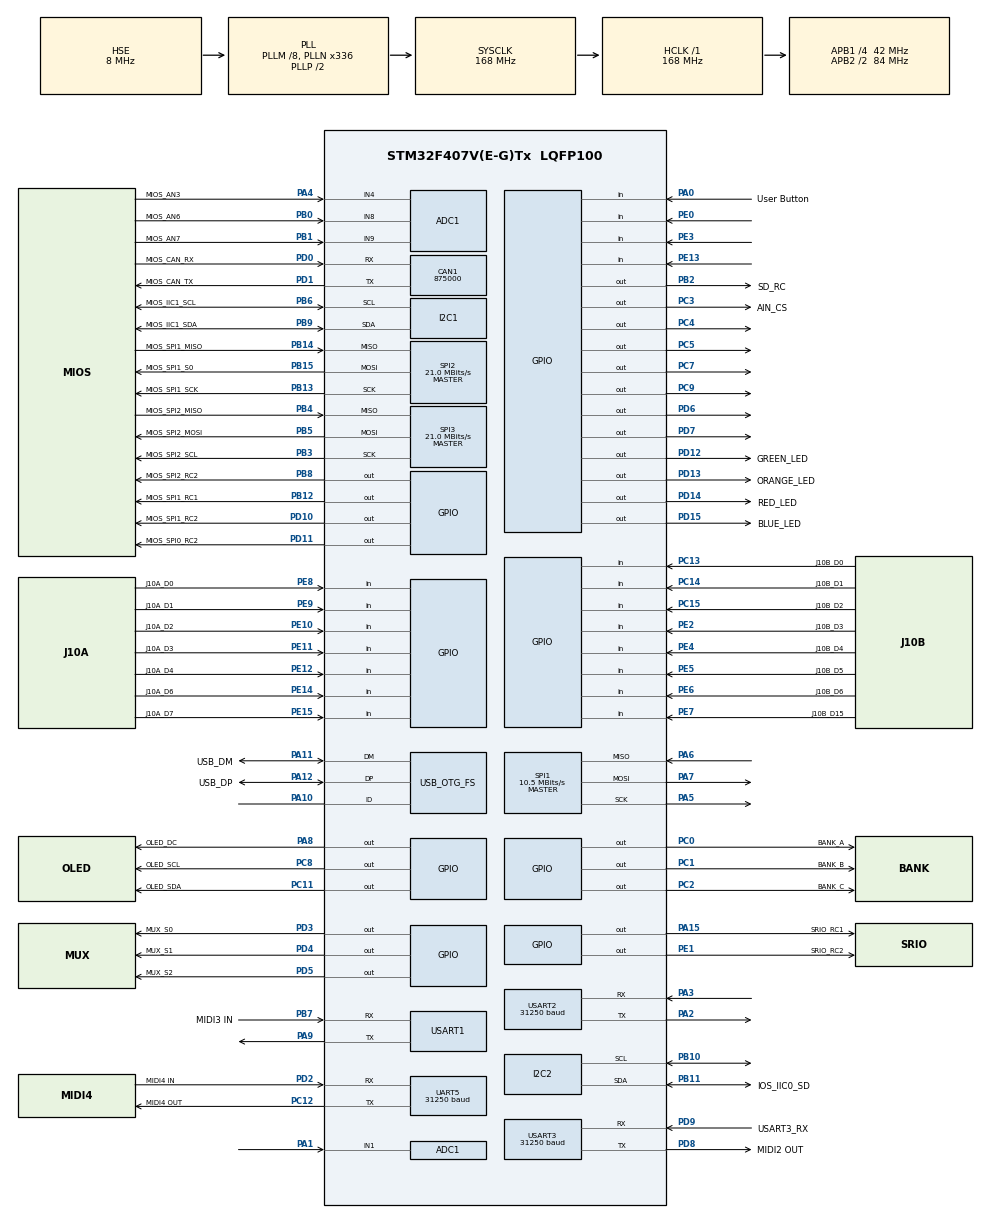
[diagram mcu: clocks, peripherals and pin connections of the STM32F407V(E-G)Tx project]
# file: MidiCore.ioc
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ADC1.Channel-0\#ChannelRegularConversion=ADC_CHANNEL_1
ADC1.NbrOfConversionFlag=1
ADC1.Rank-0\#ChannelRegularConversion=1
ADC1.SamplingTime-0\#ChannelRegularConversion=ADC_SAMPLETIME_3CYCLES
ADC1.master=1
CAN1.BS1=CAN_BS1_1TQ
CAN1.BS2=CAN_BS2_1TQ
CAN1.CalculateBaudRate=875000
CAN1.CalculateTimeBit=1142
CAN1.CalculateTimeQuantum=380.95238095238096
Dma.Request0=USART3_RX
Dma.Request1=SPI1_RX
Dma.Request2=SPI1_TX
Dma.SPI1_RX.1.Direction=DMA_PERIPH_TO_MEMORY
Dma.SPI1_RX.1.FIFOMode=DMA_FIFOMODE_DISABLE
Dma.SPI1_RX.1.Instance=DMA2_Stream0
Dma.SPI1_RX.1.MemDataAlignment=DMA_MDATAALIGN_BYTE
Dma.SPI1_RX.1.MemInc=DMA_MINC_ENABLE
Dma.SPI1_RX.1.Mode=DMA_NORMAL
Dma.SPI1_RX.1.PeriphDataAlignment=DMA_PDATAALIGN_BYTE
Dma.SPI1_RX.1.PeriphInc=DMA_PINC_DISABLE
Dma.SPI1_RX.1.Priority=DMA_PRIORITY_LOW
Dma.SPI1_TX.2.Direction=DMA_MEMORY_TO_PERIPH
Dma.SPI1_TX.2.FIFOMode=DMA_FIFOMODE_DISABLE
Dma.SPI1_TX.2.Instance=DMA2_Stream3
Dma.SPI1_TX.2.MemDataAlignment=DMA_MDATAALIGN_BYTE
Dma.SPI1_TX.2.MemInc=DMA_MINC_ENABLE
Dma.SPI1_TX.2.Mode=DMA_NORMAL
Dma.SPI1_TX.2.PeriphDataAlignment=DMA_PDATAALIGN_BYTE
Dma.SPI1_TX.2.PeriphInc=DMA_PINC_DISABLE
Dma.SPI1_TX.2.Priority=DMA_PRIORITY_LOW
Dma.USART3_RX.0.Direction=DMA_PERIPH_TO_MEMORY
Dma.USART3_RX.0.FIFOMode=DMA_FIFOMODE_DISABLE
Dma.USART3_RX.0.Instance=DMA1_Stream1
Dma.USART3_RX.0.MemDataAlignment=DMA_MDATAALIGN_BYTE
Dma.USART3_RX.0.MemInc=DMA_MINC_ENABLE
Dma.USART3_RX.0.Mode=DMA_NORMAL
Dma.USART3_RX.0.PeriphDataAlignment=DMA_PDATAALIGN_BYTE
Dma.USART3_RX.0.PeriphInc=DMA_PINC_DISABLE
Dma.USART3_RX.0.Priority=DMA_PRIORITY_LOW
FREERTOS.Tasks01=defaultTask,24,256,StartDefaultTask,Default,NULL,Dynamic,NULL,NULL
FREERTOS.configTOTAL_HEAP_SIZE=40960
FREERTOS.configUSE_MALLOC_FAILED_HOOK=0
FREERTOS.configUSE_NEWLIB_REENTRANT=1
Mcu.Family=STM32F4
Mcu.Name=STM32F407V(E-G)Tx
Mcu.Package=LQFP100
NVIC.DMA1_Stream1_IRQn=true\:5\:0\:false\:false\:true\:true\:false\:true\:true
NVIC.DMA2_Stream0_IRQn=true\:5\:0\:false\:false\:true\:true\:false\:true\:true
NVIC.DMA2_Stream3_IRQn=true\:5\:0\:false\:false\:true\:true\:false\:true\:true
NVIC.PriorityGroup=NVIC_PRIORITYGROUP_4
NVIC.TIM6_DAC_IRQn=true\:15\:0\:false\:false\:true\:false\:false\:true\:true
NVIC.TimeBase=TIM6_DAC_IRQn
NVIC.TimeBaseIP=TIM6
PA0-WKUP.GPIO_Label=User Button
PA0-WKUP.Signal=GPIO_Input
PA1.Signal=ADCx_IN1
PA10.Mode=OTG/Dual_Role_Device
PA10.Signal=USB_OTG_FS_ID
PA11.GPIO_Label=USB_DM
PA11.Mode=OTG/Dual_Role_Device
PA11.Signal=USB_OTG_FS_DM
PA12.GPIO_Label=USB_DP
PA12.Mode=OTG/Dual_Role_Device
PA12.Signal=USB_OTG_FS_DP
PA13.Mode=Serial_Wire
PA13.Signal=SYS_JTMS-SWDIO
PA14.GPIO_Label=MIOS_SPI2_RC1
PA14.Mode=Serial_Wire
PA14.Signal=SYS_JTCK-SWCLK
PA15.GPIO_Label=SRIO_RC1
PA15.Signal=GPIO_Output
PA2.Mode=Asynchronous
PA2.Signal=USART2_TX
PA3.Mode=Asynchronous
PA3.Signal=USART2_RX
PA4.GPIO_Label=MIOS_AN3
PA4.Signal=ADCx_IN4
PA5.Mode=Full_Duplex_Master
PA5.Signal=SPI1_SCK
PA6.Mode=Full_Duplex_Master
PA6.Signal=SPI1_MISO
PA7.Mode=Full_Duplex_Master
PA7.Signal=SPI1_MOSI
PA8.GPIO_Label=OLED_DC
PA8.Signal=GPIO_Output
PA9.Mode=Asynchronous
PA9.Signal=USART1_TX
PB0.GPIO_Label=MIOS_AN6
PB0.Signal=ADCx_IN8
PB1.GPIO_Label=MIOS_AN7
PB1.Signal=ADCx_IN9
PB10.Mode=I2C
PB10.Signal=I2C2_SCL
PB11.GPIO_Label=IOS_IIC0_SD
PB11.Mode=I2C
PB11.Signal=I2C2_SDA
PB12.GPIO_Label=MIOS_SPI1_RC1
PB12.Signal=GPIO_Output
PB13.GPIO_Label=MIOS_SPI1_SCK
PB13.Mode=Full_Duplex_Master
PB13.Signal=SPI2_SCK
PB14.GPIO_Label=MIOS_SPI1_MISO
PB14.Mode=Full_Duplex_Master
PB14.Signal=SPI2_MISO
PB15.GPIO_Label=MIOS_SPI1_S0
PB15.Mode=Full_Duplex_Master
PB15.Signal=SPI2_MOSI
PB2.GPIO_Label=SD_RC
PB2.Signal=GPIO_Output
PB3.GPIO_Label=MIOS_SPI2_SCL
PB3.Mode=Full_Duplex_Master
PB3.Signal=SPI3_SCK
PB4.GPIO_Label=MIOS_SPI2_MISO
PB4.Mode=Full_Duplex_Master
PB4.Signal=SPI3_MISO
PB5.GPIO_Label=MIOS_SPI2_MOSI
PB5.Mode=Full_Duplex_Master
PB5.Signal=SPI3_MOSI
PB6.GPIO_Label=MIOS_IIC1_SCL
PB6.Mode=I2C
PB6.Signal=I2C1_SCL
PB7.GPIO_Label=MIDI3 IN
PB7.Mode=Asynchronous
PB7.Signal=USART1_RX
PB8.GPIO_Label=MIOS_SPI2_RC2
PB8.Signal=GPIO_Output
PB9.GPIO_Label=MIOS_IIC1_SDA
PB9.Mode=I2C
PB9.Signal=I2C1_SDA
PC0.GPIO_Label=BANK_A
PC0.Signal=GPIO_Output
PC1.GPIO_Label=BANK_B
PC1.Signal=GPIO_Output
PC11.GPIO_Label=OLED_SDA
PC11.Signal=GPIO_Output
PC12.GPIO_Label=MIDI4 OUT
PC12.Mode=Asynchronous
PC12.Signal=UART5_TX
PC13-ANTI_TAMP.GPIO_Label=J10B_D0
PC13-ANTI_TAMP.Signal=GPIO_Input
PC14-OSC32_IN.GPIO_Label=J10B_D1
PC14-OSC32_IN.Signal=GPIO_Input
PC15-OSC32_OUT.GPIO_Label=J10B_D2
PC15-OSC32_OUT.Signal=GPIO_Input
PC2.GPIO_Label=BANK_C
PC2.Signal=GPIO_Output
PC3.GPIO_Label=AIN_CS
PC3.Signal=GPIO_Output
PC4.Signal=GPIO_Output
PC5.Signal=GPIO_Output
PC6.GPIO_Label=MIDI3 OUT
PC6.Signal=USART6_TX
PC7.Signal=GPIO_Output
PC8.GPIO_Label=OLED_SCL
PC8.Signal=GPIO_Output
PC9.Signal=GPIO_Output
PD0.GPIO_Label=MIOS_CAN_RX
PD0.Mode=CAN_Activate
PD0.Signal=CAN1_RX
PD1.GPIO_Label=MIOS_CAN_TX
PD1.Mode=CAN_Activate
PD1.Signal=CAN1_TX
PD10.GPIO_Label=MIOS_SPI1_RC2
PD10.Signal=GPIO_Output
PD11.GPIO_Label=MIOS_SPI0_RC2
PD11.Signal=GPIO_Output
PD12.GPIO_Label=GREEN_LED
PD12.Signal=GPIO_Output
PD13.GPIO_Label=ORANGE_LED
PD13.Signal=GPIO_Output
PD14.GPIO_Label=RED_LED
PD14.Signal=GPIO_Output
PD15.GPIO_Label=BLUE_LED
PD15.Signal=GPIO_Output
PD2.GPIO_Label=MIDI4 IN
PD2.Mode=Asynchronous
PD2.Signal=UART5_RX
PD3.GPIO_Label=MUX_S0
PD3.Signal=GPIO_Output
PD4.GPIO_Label=MUX_S1
PD4.Signal=GPIO_Output
PD5.GPIO_Label=MUX_S2
PD5.Signal=GPIO_Output
PD6.Signal=GPIO_Output
PD7.Signal=GPIO_Output
PD8.GPIO_Label=MIDI2 OUT
PD8.Mode=Asynchronous
PD8.Signal=USART3_TX
PD9.GPIO_Label=USART3_RX
PD9.Mode=Asynchronous
PD9.Signal=USART3_RX
PE0.Signal=GPIO_Input
PE1.GPIO_Label=SRIO_RC2
PE1.Signal=GPIO_Output
PE10.GPIO_Label=J10A_D2
PE10.Signal=GPIO_Input
PE11.GPIO_Label=J10A_D3
PE11.Signal=GPIO_Input
PE12.GPIO_Label=J10A_D4
PE12.Signal=GPIO_Input
PE13.Signal=GPIO_Input
PE14.GPIO_Label=J10A_D6
PE14.Signal=GPIO_Input
PE15.GPIO_Label=J10A_D7
PE15.Signal=GPIO_Input
PE2.GPIO_Label=J10B_D3
PE2.Signal=GPIO_Input
PE3.Signal=GPIO_Input
PE4.GPIO_Label=J10B_D4
PE4.Signal=GPIO_Input
PE5.GPIO_Label=J10B_D5
PE5.Signal=GPIO_Input
PE6.GPIO_Label=J10B_D6
PE6.Signal=GPIO_Input
PE7.GPIO_Label=J10B_D15
PE7.Signal=GPIO_Input
PE8.GPIO_Label=J10A_D0
PE8.Signal=GPIO_Input
PE9.GPIO_Label=J10A_D1
PE9.Signal=GPIO_Input
PH0-OSC_IN.Mode=HSE-External-Oscillator
PH0-OSC_IN.Signal=RCC_OSC_IN
PH1-OSC_OUT.Mode=HSE-External-Oscillator
PH1-OSC_OUT.Signal=RCC_OSC_OUT
ProjectManager.HeapSize=0x200
ProjectManager.StackSize=0x400
ProjectManager.TargetToolchain=STM32CubeIDE
RCC.48MHZClocksFreq_Value=48000000
RCC.AHBFreq_Value=168000000
RCC.APB1CLKDivider=RCC_HCLK_DIV4
RCC.APB1Freq_Value=42000000
RCC.APB1TimFreq_Value=84000000
RCC.APB2CLKDivider=RCC_HCLK_DIV2
RCC.APB2Freq_Value=84000000
RCC.APB2TimFreq_Value=168000000
RCC.CortexFreq_Value=168000000
RCC.EnbaleCSS=true
RCC.HCLKFreq_Value=168000000
RCC.HSE_VALUE=8000000
RCC.HSI_VALUE=16000000
RCC.LSE_VALUE=32768
RCC.PLLM=8
RCC.PLLN=336
RCC.PLLQ=7
RCC.PLLSourceVirtual=RCC_PLLSOURCE_HSE
RCC.SYSCLKFreq_VALUE=168000000
RCC.SYSCLKSource=RCC_SYSCLKSOURCE_PLLCLK
RCC.VCOOutputFreq_Value=336000000
SH.ADCx_IN1.0=ADC1_IN1,IN1
SH.ADCx_IN4.0=ADC1_IN4,IN4
SH.ADCx_IN8.0=ADC1_IN8,IN8
SH.ADCx_IN9.0=ADC1_IN9,IN9
SPI1.BaudRatePrescaler=SPI_BAUDRATEPRESCALER_8
SPI1.CalculateBaudRate=10.5 MBits/s
SPI1.Direction=SPI_DIRECTION_2LINES
SPI1.Mode=SPI_MODE_MASTER
SPI1.VirtualType=VM_MASTER
SPI2.BaudRatePrescaler=SPI_BAUDRATEPRESCALER_2
SPI2.CalculateBaudRate=21.0 MBits/s
SPI2.Direction=SPI_DIRECTION_2LINES
SPI2.Mode=SPI_MODE_MASTER
SPI2.VirtualType=VM_MASTER
SPI3.BaudRatePrescaler=SPI_BAUDRATEPRESCALER_2
SPI3.CalculateBaudRate=21.0 MBits/s
SPI3.Direction=SPI_DIRECTION_2LINES
SPI3.Mode=SPI_MODE_MASTER
SPI3.VirtualType=VM_MASTER
UART5.BaudRate=31250
UART5.VirtualMode=Asynchronous
USART1.VirtualMode=VM_ASYNC
USART2.BaudRate=31250
USART2.VirtualMode=VM_ASYNC
USART3.BaudRate=31250
USART3.VirtualMode=VM_ASYNC
VP_FATFS_VS_Generic.Mode=User_defined
VP_FREERTOS_VS_CMSIS_V2.Mode=CMSIS_V2
VP_SYS_VS_tim6.Mode=TIM6
VP_TIM2_VS_ClockSourceINT.Mode=Internal
board=custom

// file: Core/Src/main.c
/* USER CODE BEGIN Header */
/**
  ******************************************************************************
  * @file           : main.c
  * @brief          : Main program body
  ******************************************************************************
  * @attention
  *
  * Copyright (c) 2026 STMicroelectronics.
  * All rights reserved.
  *
  * This software is licensed under terms that can be found in the LICENSE file
  * in the root directory of this software component.
  * If no LICENSE file comes with this software, it is provided AS-IS.
  *
  ******************************************************************************
  */
/* USER CODE END Header */
#include "main.h"
#include "cmsis_os.h"
#include "fatfs.h"
#include "usb_host.h"

/* USER CODE BEGIN Includes */
#include "Config/module_config.h"  // MUST be first to define MODULE_ENABLE_* macros
#include "App/app_entry.h"
#include "Config/oled_pins.h"

#include "App/tests/test_debug.h"  // For TEST_DEBUG_UART_BAUD configuration
#include "App/tests/app_test_din_midi.h"
#include "App/tests/app_test_ainser_midi.h"
#include "App/tests/module_tests.h"
#include "Services/usb_host_midi/usb_host_midi.h"
/* USER CODE END Includes */

ADC_HandleTypeDef hadc1;

CAN_HandleTypeDef hcan1;

I2C_HandleTypeDef hi2c1;
I2C_HandleTypeDef hi2c2;

SPI_HandleTypeDef hspi1;
SPI_HandleTypeDef hspi2;
SPI_HandleTypeDef hspi3;
DMA_HandleTypeDef hdma_spi1_rx;
DMA_HandleTypeDef hdma_spi1_tx;

TIM_HandleTypeDef htim2;

UART_HandleTypeDef huart5;
UART_HandleTypeDef huart1;
UART_HandleTypeDef huart2;
UART_HandleTypeDef huart3;
DMA_HandleTypeDef hdma_usart3_rx;

/* Definitions for defaultTask */
osThreadId_t defaultTaskHandle;
const osThreadAttr_t defaultTask_attributes = {
  .name = "defaultTask",
  .stack_size = 2048,  // 2KB - Adequate for init sequence before entering idle loop
                       // USB Host init (~500B) + module test init (~300B) + app_entry_start() chain (~800B) + margin (~448B)
                       // Reduced from 16KB (prevents fragmentation) but not too small to cause overflow (512B was insufficient)
                       // This is the safe middle ground: prevents overflow while saving 14KB vs original
  .priority = (osPriority_t) osPriorityNormal,
};

void SystemClock_Config(void);
static void MX_GPIO_Init(void);
static void MX_DMA_Init(void);
static void MX_SPI1_Init(void);
static void MX_TIM2_Init(void);
static void MX_USART3_UART_Init(void);
static void MX_I2C2_Init(void);
static void MX_SPI3_Init(void);
static void MX_UART5_Init(void);
static void MX_USART1_UART_Init(void);
static void MX_USART2_UART_Init(void);
static void MX_SPI2_Init(void);
static void MX_ADC1_Init(void);
static void MX_CAN1_Init(void);
static void MX_I2C1_Init(void);
void StartDefaultTask(void *argument);

int main(void)
{

  /* MCU Configuration--------------------------------------------------------*/

  /* Reset of all peripherals, Initializes the Flash interface and the Systick. */
  HAL_Init();

  /* Configure the system clock */
  SystemClock_Config();

  /* Initialize all configured peripherals */
  MX_GPIO_Init();
  MX_DMA_Init();
  MX_SPI1_Init();
  MX_TIM2_Init();
  MX_USART3_UART_Init();
  MX_I2C2_Init();
  MX_SPI3_Init();
  MX_UART5_Init();
  MX_USART1_UART_Init();
  MX_USART2_UART_Init();
  MX_SPI2_Init();
  MX_FATFS_Init();
  MX_ADC1_Init();
  MX_CAN1_Init();
  MX_I2C1_Init();
  /* USER CODE BEGIN 2 */

  /* Enable CCMRAM clock - CRITICAL for accessing CCMRAM variables!
   * Without this, any access to CCMRAM (0x10000000) will cause HardFault.
   * Must be called before FreeRTOS starts (osKernelInitialize) because
   * startup code zeros CCMRAM section and tasks may access CCMRAM variables.
   */
  __HAL_RCC_CCMDATARAMEN_CLK_ENABLE();

#if MODULE_ENABLE_USB_MIDI || MODULE_ENABLE_USB_CDC
  /* CRITICAL FIX: Register interface callbacks BEFORE starting USB device!
   *
   * The callbacks MUST be registered before MX_USB_DEVICE_Init() because:
   * - MX_USB_DEVICE_Init() calls USBD_Start() which triggers USB enumeration
   * - During enumeration, host sends SET_CONFIGURATION
   * - This calls USBD_COMPOSITE_Init() → USBD_MIDI.Init() and USBD_CDC.Init()
   * - Those Init functions expect callbacks to already be registered
   * - If callbacks are NULL, DataOut/Receive will never be called!
   *
   * OLD (BROKEN) ORDER:
   *   1. MX_USB_DEVICE_Init() → enumeration starts → callbacks NULL
   *   2. usb_midi_init() → too late, already enumerated
   *   3. usb_cdc_init() → too late, already enumerated
   *
   * NEW (CORRECT) ORDER:
   *   1. router_init() → MIDI router must be ready FIRST
   *   2. usb_midi_init() → register callbacks
   *   3. usb_cdc_init() → register callbacks
   *   4. MX_USB_DEVICE_Init() → NOW start enumeration with callbacks ready
   */

  #if MODULE_ENABLE_ROUTER
    /* CRITICAL: Initialize router BEFORE USB MIDI!
     * USB MIDI callbacks call router_process() which requires g_send to be set.
     * Without this, receiving USB MIDI data causes HardFault (NULL/garbage function pointer).
     */
    extern int router_send_default(uint8_t out_node, const void* msg);
    extern void router_init(void* send_cb);
    router_init(router_send_default);
  #endif

  #if MODULE_ENABLE_USB_MIDI
    /* Initialize MIDI service and register interface callbacks */
    extern void usb_midi_init(void);
    usb_midi_init();
  #endif

  #if MODULE_ENABLE_USB_CDC
    /* Initialize CDC service and register interface callbacks */
    extern void usb_cdc_init(void);
    usb_cdc_init();
  #endif

  /* NOW start USB device with callbacks already registered */
  MX_USB_DEVICE_Init();
#endif
  /* USER CODE END 2 */

  /* Init scheduler */
  osKernelInitialize();

  /* USER CODE BEGIN RTOS_MUTEX */
  /* Initialize SPI bus abstraction layer AFTER FreeRTOS kernel init
   * (requires osMutexNew which needs FreeRTOS running)
   */
  extern void spibus_init(void);
  spibus_init();
  /* USER CODE END RTOS_MUTEX */

  /* Create the thread(s) */
  /* creation of defaultTask */
  defaultTaskHandle = osThreadNew(StartDefaultTask, NULL, &defaultTask_attributes);

  /* USER CODE BEGIN RTOS_THREADS */
  /* Verify DefaultTask was created successfully */
  if (defaultTaskHandle == NULL) {
    /* CRITICAL: DefaultTask creation failed - likely heap exhaustion */
    /* This will be caught before scheduler starts */
    Error_Handler();
  }
  /* add threads, ... */
  /* USER CODE END RTOS_THREADS */

  /* Start scheduler */
  osKernelStart();

  /* We should never get here as control is now taken by the scheduler */

  /* Infinite loop */
  while (1)
  {

  }
}

void SystemClock_Config(void)
{
  RCC_OscInitTypeDef RCC_OscInitStruct = {0};
  RCC_ClkInitTypeDef RCC_ClkInitStruct = {0};

  /** Configure the main internal regulator output voltage
  */
  __HAL_RCC_PWR_CLK_ENABLE();
  __HAL_PWR_VOLTAGESCALING_CONFIG(PWR_REGULATOR_VOLTAGE_SCALE1);

  /** Initializes the RCC Oscillators according to the specified parameters
  * in the RCC_OscInitTypeDef structure.
  */
  RCC_OscInitStruct.OscillatorType = RCC_OSCILLATORTYPE_HSE;
  RCC_OscInitStruct.HSEState = RCC_HSE_ON;
  RCC_OscInitStruct.PLL.PLLState = RCC_PLL_ON;
  RCC_OscInitStruct.PLL.PLLSource = RCC_PLLSOURCE_HSE;
  RCC_OscInitStruct.PLL.PLLM = 8;
  RCC_OscInitStruct.PLL.PLLN = 336;
  RCC_OscInitStruct.PLL.PLLP = RCC_PLLP_DIV2;
  RCC_OscInitStruct.PLL.PLLQ = 7;
  if (HAL_RCC_OscConfig(&RCC_OscInitStruct) != HAL_OK)
  {
    Error_Handler();
  }

  /** Initializes the CPU, AHB and APB buses clocks
  */
  RCC_ClkInitStruct.ClockType = RCC_CLOCKTYPE_HCLK|RCC_CLOCKTYPE_SYSCLK
                              |RCC_CLOCKTYPE_PCLK1|RCC_CLOCKTYPE_PCLK2;
  RCC_ClkInitStruct.SYSCLKSource = RCC_SYSCLKSOURCE_PLLCLK;
  RCC_ClkInitStruct.AHBCLKDivider = RCC_SYSCLK_DIV1;
  RCC_ClkInitStruct.APB1CLKDivider = RCC_HCLK_DIV4;
  RCC_ClkInitStruct.APB2CLKDivider = RCC_HCLK_DIV2;

  if (HAL_RCC_ClockConfig(&RCC_ClkInitStruct, FLASH_LATENCY_5) != HAL_OK)
  {
    Error_Handler();
  }

  /** Enables the Clock Security System
  */
  HAL_RCC_EnableCSS();
}

static void MX_ADC1_Init(void)
{

  ADC_ChannelConfTypeDef sConfig = {0};

  /** Configure the global features of the ADC (Clock, Resolution, Data Alignment and number of conversion)
  */
  hadc1.Instance = ADC1;
  hadc1.Init.ClockPrescaler = ADC_CLOCK_SYNC_PCLK_DIV4;
  hadc1.Init.Resolution = ADC_RESOLUTION_12B;
  hadc1.Init.ScanConvMode = DISABLE;
  hadc1.Init.ContinuousConvMode = DISABLE;
  hadc1.Init.DiscontinuousConvMode = DISABLE;
  hadc1.Init.ExternalTrigConvEdge = ADC_EXTERNALTRIGCONVEDGE_NONE;
  hadc1.Init.ExternalTrigConv = ADC_SOFTWARE_START;
  hadc1.Init.DataAlign = ADC_DATAALIGN_RIGHT;
  hadc1.Init.NbrOfConversion = 1;
  hadc1.Init.DMAContinuousRequests = DISABLE;
  hadc1.Init.EOCSelection = ADC_EOC_SINGLE_CONV;
  if (HAL_ADC_Init(&hadc1) != HAL_OK)
  {
    Error_Handler();
  }

  /** Configure for the selected ADC regular channel its corresponding rank in the sequencer and its sample time.
  */
  sConfig.Channel = ADC_CHANNEL_1;
  sConfig.Rank = 1;
  sConfig.SamplingTime = ADC_SAMPLETIME_3CYCLES;
  if (HAL_ADC_ConfigChannel(&hadc1, &sConfig) != HAL_OK)
  {
    Error_Handler();
  }

}

static void MX_CAN1_Init(void)
{

  hcan1.Instance = CAN1;
  hcan1.Init.Prescaler = 16;
  hcan1.Init.Mode = CAN_MODE_NORMAL;
  hcan1.Init.SyncJumpWidth = CAN_SJW_1TQ;
  hcan1.Init.TimeSeg1 = CAN_BS1_1TQ;
  hcan1.Init.TimeSeg2 = CAN_BS2_1TQ;
  hcan1.Init.TimeTriggeredMode = DISABLE;
  hcan1.Init.AutoBusOff = DISABLE;
  hcan1.Init.AutoWakeUp = DISABLE;
  hcan1.Init.AutoRetransmission = DISABLE;
  hcan1.Init.ReceiveFifoLocked = DISABLE;
  hcan1.Init.TransmitFifoPriority = DISABLE;
  if (HAL_CAN_Init(&hcan1) != HAL_OK)
  {
    Error_Handler();
  }

}

static void MX_I2C1_Init(void)
{

  hi2c1.Instance = I2C1;
  hi2c1.Init.ClockSpeed = 100000;
  hi2c1.Init.DutyCycle = I2C_DUTYCYCLE_2;
  hi2c1.Init.OwnAddress1 = 0;
  hi2c1.Init.AddressingMode = I2C_ADDRESSINGMODE_7BIT;
  hi2c1.Init.DualAddressMode = I2C_DUALADDRESS_DISABLE;
  hi2c1.Init.OwnAddress2 = 0;
  hi2c1.Init.GeneralCallMode = I2C_GENERALCALL_DISABLE;
  hi2c1.Init.NoStretchMode = I2C_NOSTRETCH_DISABLE;
  if (HAL_I2C_Init(&hi2c1) != HAL_OK)
  {
    Error_Handler();
  }

}

static void MX_I2C2_Init(void)
{

  hi2c2.Instance = I2C2;
  hi2c2.Init.ClockSpeed = 100000;
  hi2c2.Init.DutyCycle = I2C_DUTYCYCLE_2;
  hi2c2.Init.OwnAddress1 = 0;
  hi2c2.Init.AddressingMode = I2C_ADDRESSINGMODE_7BIT;
  hi2c2.Init.DualAddressMode = I2C_DUALADDRESS_DISABLE;
  hi2c2.Init.OwnAddress2 = 0;
  hi2c2.Init.GeneralCallMode = I2C_GENERALCALL_DISABLE;
  hi2c2.Init.NoStretchMode = I2C_NOSTRETCH_DISABLE;
  if (HAL_I2C_Init(&hi2c2) != HAL_OK)
  {
    Error_Handler();
  }

}

static void MX_SPI1_Init(void)
{

  /* SPI1 parameter configuration*/
  hspi1.Instance = SPI1;
  hspi1.Init.Mode = SPI_MODE_MASTER;
  hspi1.Init.Direction = SPI_DIRECTION_2LINES;
  hspi1.Init.DataSize = SPI_DATASIZE_8BIT;
  hspi1.Init.CLKPolarity = SPI_POLARITY_LOW;
  hspi1.Init.CLKPhase = SPI_PHASE_1EDGE;
  hspi1.Init.NSS = SPI_NSS_SOFT;
  hspi1.Init.BaudRatePrescaler = SPI_BAUDRATEPRESCALER_8;
  hspi1.Init.FirstBit = SPI_FIRSTBIT_MSB;
  hspi1.Init.TIMode = SPI_TIMODE_DISABLE;
  hspi1.Init.CRCCalculation = SPI_CRCCALCULATION_DISABLE;
  hspi1.Init.CRCPolynomial = 10;
  if (HAL_SPI_Init(&hspi1) != HAL_OK)
  {
    Error_Handler();
  }

}

static void MX_SPI2_Init(void)
{

  /* SPI2 parameter configuration*/
  hspi2.Instance = SPI2;
  hspi2.Init.Mode = SPI_MODE_MASTER;
  hspi2.Init.Direction = SPI_DIRECTION_2LINES;
  hspi2.Init.DataSize = SPI_DATASIZE_8BIT;
  hspi2.Init.CLKPolarity = SPI_POLARITY_LOW;
  hspi2.Init.CLKPhase = SPI_PHASE_1EDGE;
  hspi2.Init.NSS = SPI_NSS_SOFT;
  hspi2.Init.BaudRatePrescaler = SPI_BAUDRATEPRESCALER_2;
  hspi2.Init.FirstBit = SPI_FIRSTBIT_MSB;
  hspi2.Init.TIMode = SPI_TIMODE_DISABLE;
  hspi2.Init.CRCCalculation = SPI_CRCCALCULATION_DISABLE;
  hspi2.Init.CRCPolynomial = 10;
  if (HAL_SPI_Init(&hspi2) != HAL_OK)
  {
    Error_Handler();
  }

}

static void MX_SPI3_Init(void)
{

  /* SPI3 parameter configuration*/
  hspi3.Instance = SPI3;
  hspi3.Init.Mode = SPI_MODE_MASTER;
  hspi3.Init.Direction = SPI_DIRECTION_2LINES;
  hspi3.Init.DataSize = SPI_DATASIZE_8BIT;
  hspi3.Init.CLKPolarity = SPI_POLARITY_LOW;
  hspi3.Init.CLKPhase = SPI_PHASE_1EDGE;
  hspi3.Init.NSS = SPI_NSS_SOFT;
  hspi3.Init.BaudRatePrescaler = SPI_BAUDRATEPRESCALER_2;
  hspi3.Init.FirstBit = SPI_FIRSTBIT_MSB;
  hspi3.Init.TIMode = SPI_TIMODE_DISABLE;
  hspi3.Init.CRCCalculation = SPI_CRCCALCULATION_DISABLE;
  hspi3.Init.CRCPolynomial = 10;
  if (HAL_SPI_Init(&hspi3) != HAL_OK)
  {
    Error_Handler();
  }

}

static void MX_TIM2_Init(void)
{

  TIM_ClockConfigTypeDef sClockSourceConfig = {0};
  TIM_MasterConfigTypeDef sMasterConfig = {0};

  htim2.Instance = TIM2;
  htim2.Init.Prescaler = 0;
  htim2.Init.CounterMode = TIM_COUNTERMODE_UP;
  htim2.Init.Period = 4294967295;
  htim2.Init.ClockDivision = TIM_CLOCKDIVISION_DIV1;
  htim2.Init.AutoReloadPreload = TIM_AUTORELOAD_PRELOAD_DISABLE;
  if (HAL_TIM_Base_Init(&htim2) != HAL_OK)
  {
    Error_Handler();
  }
  sClockSourceConfig.ClockSource = TIM_CLOCKSOURCE_INTERNAL;
  if (HAL_TIM_ConfigClockSource(&htim2, &sClockSourceConfig) != HAL_OK)
  {
    Error_Handler();
  }
  sMasterConfig.MasterOutputTrigger = TIM_TRGO_RESET;
  sMasterConfig.MasterSlaveMode = TIM_MASTERSLAVEMODE_DISABLE;
  if (HAL_TIMEx_MasterConfigSynchronization(&htim2, &sMasterConfig) != HAL_OK)
  {
    Error_Handler();
  }

}

static void MX_UART5_Init(void)
{

  huart5.Instance = UART5;
  /* USER CODE BEGIN UART5_BaudRate */
  // If debug UART is mapped to port 3, run UART5 at TEST_DEBUG_UART_BAUD for terminal
  #ifdef TEST_DEBUG_UART_BAUD
    #if TEST_DEBUG_UART_PORT == 3
      huart5.Init.BaudRate = TEST_DEBUG_UART_BAUD;
    #else
      huart5.Init.BaudRate = 31250;   // MIDI baudrate otherwise
    #endif
  #else
    huart5.Init.BaudRate = 31250;     // Default MIDI baudrate
  #endif
  /* USER CODE END UART5_BaudRate */
  huart5.Init.WordLength = UART_WORDLENGTH_8B;
  huart5.Init.StopBits = UART_STOPBITS_1;
  huart5.Init.Parity = UART_PARITY_NONE;
  huart5.Init.Mode = UART_MODE_TX_RX;
  huart5.Init.HwFlowCtl = UART_HWCONTROL_NONE;
  huart5.Init.OverSampling = UART_OVERSAMPLING_16;
  if (HAL_UART_Init(&huart5) != HAL_OK)
  {
    Error_Handler();
  }

}

static void MX_USART1_UART_Init(void)
{

  huart1.Instance = USART1;
  huart1.Init.BaudRate = 115200;
  huart1.Init.WordLength = UART_WORDLENGTH_8B;
  huart1.Init.StopBits = UART_STOPBITS_1;
  huart1.Init.Parity = UART_PARITY_NONE;
  huart1.Init.Mode = UART_MODE_TX_RX;
  huart1.Init.HwFlowCtl = UART_HWCONTROL_NONE;
  huart1.Init.OverSampling = UART_OVERSAMPLING_16;
  if (HAL_UART_Init(&huart1) != HAL_OK)
  {
    Error_Handler();
  }

}

static void MX_USART2_UART_Init(void)
{

  huart2.Instance = USART2;

  /* USER CODE BEGIN USART2_BaudRate */
  // UART2 baud rate: Use TEST_DEBUG_UART_BAUD if test_debug.h is included,
  // otherwise default to 31250 (MIDI)
  // This ensures UART2 is at 115200 when any test using dbg_print() is active
  #ifdef TEST_DEBUG_UART_BAUD
    #if TEST_DEBUG_UART_PORT == 1
      huart2.Init.BaudRate = TEST_DEBUG_UART_BAUD;  // Use configured debug baud rate (typically 115200)
    #else
      huart2.Init.BaudRate = 31250;   // UART2 used for MIDI, not debug
    #endif
  #else
    huart2.Init.BaudRate = 31250;   // Default MIDI baud rate for production
  #endif
  /* USER CODE END USART2_BaudRate */

  huart2.Init.WordLength = UART_WORDLENGTH_8B;
  huart2.Init.StopBits = UART_STOPBITS_1;
  huart2.Init.Parity = UART_PARITY_NONE;
  huart2.Init.Mode = UART_MODE_TX_RX;
  huart2.Init.HwFlowCtl = UART_HWCONTROL_NONE;
  huart2.Init.OverSampling = UART_OVERSAMPLING_16;
  if (HAL_UART_Init(&huart2) != HAL_OK)
  {
    Error_Handler();
  }

}

static void MX_USART3_UART_Init(void)
{

  huart3.Instance = USART3;
  /* USER CODE BEGIN USART3_BaudRate */
  // If debug UART is mapped to port 1, run USART3 at TEST_DEBUG_UART_BAUD for terminal
  #ifdef TEST_DEBUG_UART_BAUD
    #if TEST_DEBUG_UART_PORT == 1
      huart3.Init.BaudRate = TEST_DEBUG_UART_BAUD;
    #else
      huart3.Init.BaudRate = 31250;  // MIDI baud otherwise
    #endif
  #else
    huart3.Init.BaudRate = 31250;
  #endif
  /* USER CODE END USART3_BaudRate */
  huart3.Init.WordLength = UART_WORDLENGTH_8B;
  huart3.Init.StopBits = UART_STOPBITS_1;
  huart3.Init.Parity = UART_PARITY_NONE;
  huart3.Init.Mode = UART_MODE_TX_RX;
  huart3.Init.HwFlowCtl = UART_HWCONTROL_NONE;
  huart3.Init.OverSampling = UART_OVERSAMPLING_16;
  if (HAL_UART_Init(&huart3) != HAL_OK)
  {
    Error_Handler();
  }

}

static void MX_DMA_Init(void)
{

  /* DMA controller clock enable */
  __HAL_RCC_DMA1_CLK_ENABLE();
  __HAL_RCC_DMA2_CLK_ENABLE();

  /* DMA interrupt init */
  /* DMA1_Stream1_IRQn interrupt configuration */
  HAL_NVIC_SetPriority(DMA1_Stream1_IRQn, 5, 0);
  HAL_NVIC_EnableIRQ(DMA1_Stream1_IRQn);
  /* DMA2_Stream0_IRQn interrupt configuration */
  HAL_NVIC_SetPriority(DMA2_Stream0_IRQn, 5, 0);
  HAL_NVIC_EnableIRQ(DMA2_Stream0_IRQn);
  /* DMA2_Stream3_IRQn interrupt configuration */
  HAL_NVIC_SetPriority(DMA2_Stream3_IRQn, 5, 0);
  HAL_NVIC_EnableIRQ(DMA2_Stream3_IRQn);

}

static void MX_GPIO_Init(void)
{
  GPIO_InitTypeDef GPIO_InitStruct = {0};

  /* GPIO Ports Clock Enable */
  __HAL_RCC_GPIOE_CLK_ENABLE();
  __HAL_RCC_GPIOC_CLK_ENABLE();
  __HAL_RCC_GPIOH_CLK_ENABLE();
  __HAL_RCC_GPIOA_CLK_ENABLE();
  __HAL_RCC_GPIOB_CLK_ENABLE();
  __HAL_RCC_GPIOD_CLK_ENABLE();

  /*Configure GPIO pin Output Level */
  HAL_GPIO_WritePin(GPIOC, BANK_A_Pin|BANK_B_Pin|BANK_C_Pin|AIN_CS_Pin
                          |OLED_SCL_Pin|GPIO_PIN_7|GPIO_PIN_8
                          |GPIO_PIN_9|OLED_SDA_Pin, GPIO_PIN_RESET);

  /*Configure GPIO pin Output Level */
  HAL_GPIO_WritePin(GPIOB, MIOS_SPI0_RC1_Pin|SRIO_DOUT_RCLK_Pin|MIOS_SPI2_RC2_Pin, GPIO_PIN_RESET);

  /*Configure GPIO pin Output Level */
  HAL_GPIO_WritePin(GPIOD, MIOS_SPI1_RC2_Pin|MIOS_SPI0_RC2_Pin|GREEN_LED_Pin|ORANGE_LED_Pin
                          |RED_LED_Pin|BLUE_LED_Pin|MUX_S0_Pin|MUX_S1_Pin
                          |MUX_S2_Pin|GPIO_PIN_6|GPIO_PIN_7, GPIO_PIN_RESET);

  /*Configure GPIO pin Output Level */
  HAL_GPIO_WritePin(GPIOA, OLED_DC_Pin|SRIO_RC1_Pin|GPIO_PIN_4, GPIO_PIN_RESET);  // Added PA4 for SD_CS

  /*Configure GPIO pin Output Level */
  HAL_GPIO_WritePin(SRIO_RC2_GPIO_Port, SRIO_RC2_Pin, GPIO_PIN_RESET);

  /*Configure GPIO pins : J10B_D3_Pin PE3 J10B_D4_Pin J10B_D5_Pin
                           J10B_D6_Pin J10B_D15_Pin J10A_D0_Pin J10A_D1_Pin
                           J10A_D2_Pin J10A_D3_Pin J10A_D4_Pin PE13
                           J10A_D6_Pin J10A_D7_Pin PE0 */
  GPIO_InitStruct.Pin = J10B_D3_Pin|GPIO_PIN_3|J10B_D4_Pin|J10B_D5_Pin
                          |J10B_D6_Pin|J10B_D15_Pin|J10A_D0_Pin|J10A_D1_Pin
                          |J10A_D2_Pin|J10A_D3_Pin|J10A_D4_Pin|GPIO_PIN_13
                          |J10A_D6_Pin|J10A_D7_Pin|GPIO_PIN_0;
  GPIO_InitStruct.Mode = GPIO_MODE_INPUT;
  GPIO_InitStruct.Pull = GPIO_NOPULL;
  HAL_GPIO_Init(GPIOE, &GPIO_InitStruct);

  /*Configure GPIO pins : J10B_D0_Pin J10B_D1_Pin J10B_D2_Pin */
  GPIO_InitStruct.Pin = J10B_D0_Pin|J10B_D1_Pin|J10B_D2_Pin;
  GPIO_InitStruct.Mode = GPIO_MODE_INPUT;
  GPIO_InitStruct.Pull = GPIO_NOPULL;
  HAL_GPIO_Init(GPIOC, &GPIO_InitStruct);

  /*Configure GPIO pins : BANK_A_Pin BANK_B_Pin BANK_C_Pin AIN_CS_Pin
                           OLED_SCL_Pin PC7 PC9 OLED_SDA_Pin */
  GPIO_InitStruct.Pin = BANK_A_Pin|BANK_B_Pin|BANK_C_Pin|AIN_CS_Pin
                          |OLED_SCL_Pin|GPIO_PIN_7|GPIO_PIN_9|OLED_SDA_Pin;
  GPIO_InitStruct.Mode = GPIO_MODE_OUTPUT_PP;
  GPIO_InitStruct.Pull = GPIO_NOPULL;
  GPIO_InitStruct.Speed = GPIO_SPEED_FREQ_VERY_HIGH;  // Fast speed for OLED communication
  HAL_GPIO_Init(GPIOC, &GPIO_InitStruct);

  /*Configure GPIO pin : User_Button_Pin */
  GPIO_InitStruct.Pin = User_Button_Pin;
  GPIO_InitStruct.Mode = GPIO_MODE_INPUT;
  GPIO_InitStruct.Pull = GPIO_NOPULL;
  HAL_GPIO_Init(User_Button_GPIO_Port, &GPIO_InitStruct);

  /*Configure GPIO pins : MIOS_SPI0_RC1_Pin SRIO_DOUT_RCLK_Pin MIOS_SPI2_RC2_Pin */
  GPIO_InitStruct.Pin = MIOS_SPI0_RC1_Pin|SRIO_DOUT_RCLK_Pin|MIOS_SPI2_RC2_Pin;
  GPIO_InitStruct.Mode = GPIO_MODE_OUTPUT_PP;
  GPIO_InitStruct.Pull = GPIO_NOPULL;
  GPIO_InitStruct.Speed = GPIO_SPEED_FREQ_LOW;
  HAL_GPIO_Init(GPIOB, &GPIO_InitStruct);

  /*Configure GPIO pins : MIOS_SPI1_RC2_Pin MIOS_SPI0_RC2_Pin GREEN_LED_Pin ORANGE_LED_Pin
                           RED_LED_Pin BLUE_LED_Pin MUX_S0_Pin MUX_S1_Pin
                           MUX_S2_Pin PD6 PD7 */
  GPIO_InitStruct.Pin = MIOS_SPI1_RC2_Pin|MIOS_SPI0_RC2_Pin|GREEN_LED_Pin|ORANGE_LED_Pin
                          |RED_LED_Pin|BLUE_LED_Pin|MUX_S0_Pin|MUX_S1_Pin
                          |MUX_S2_Pin|GPIO_PIN_6|GPIO_PIN_7;
  GPIO_InitStruct.Mode = GPIO_MODE_OUTPUT_PP;
  GPIO_InitStruct.Pull = GPIO_NOPULL;
  GPIO_InitStruct.Speed = GPIO_SPEED_FREQ_LOW;
  HAL_GPIO_Init(GPIOD, &GPIO_InitStruct);

  /*Configure GPIO pin : MIDI3_OUT_Pin */
  GPIO_InitStruct.Pin = MIDI3_OUT_Pin;
  GPIO_InitStruct.Mode = GPIO_MODE_AF_PP;
  GPIO_InitStruct.Pull = GPIO_NOPULL;
  GPIO_InitStruct.Speed = GPIO_SPEED_FREQ_VERY_HIGH;
  GPIO_InitStruct.Alternate = GPIO_AF8_USART6;
  HAL_GPIO_Init(MIDI3_OUT_GPIO_Port, &GPIO_InitStruct);

  /*Configure GPIO pins : OLED_DC_Pin SRIO_RC1_Pin PA4 (SD_CS) */
  GPIO_InitStruct.Pin = OLED_DC_Pin|SRIO_RC1_Pin|GPIO_PIN_4;  // Added PA4 for SD card CS
  GPIO_InitStruct.Mode = GPIO_MODE_OUTPUT_PP;
  GPIO_InitStruct.Pull = GPIO_NOPULL;
  GPIO_InitStruct.Speed = GPIO_SPEED_FREQ_VERY_HIGH;  // Fast speed for OLED DC signal
  HAL_GPIO_Init(GPIOA, &GPIO_InitStruct);

  /*Configure GPIO pin : SRIO_RC2_Pin */
  GPIO_InitStruct.Pin = SRIO_RC2_Pin;
  GPIO_InitStruct.Mode = GPIO_MODE_OUTPUT_PP;
  GPIO_InitStruct.Pull = GPIO_NOPULL;
  GPIO_InitStruct.Speed = GPIO_SPEED_FREQ_LOW;
  HAL_GPIO_Init(SRIO_RC2_GPIO_Port, &GPIO_InitStruct);

}

/* USER CODE BEGIN Header_StartDefaultTask */
/**
 * @brief  Main production task implementing the defaultTask thread.
 *
 * This is the definitive production entry point for MidiCore.
 * It initializes USB Host MIDI and starts the main application.
 *
 * For module testing, define MODULE_TEST_xxx at compile time to run
 * specific module tests instead of the full application.
 *
 * @param  argument: Not used
 * @retval None
 */
/* USER CODE END Header_StartDefaultTask */
void StartDefaultTask(void *argument)
{
  /* USER CODE BEGIN 5 */

  /* init code for USB_HOST - only if enabled */
#if MODULE_ENABLE_USBH_MIDI
  MX_USB_HOST_Init();
  // Init USB Host MIDI wrapper
  usb_host_midi_init();
#endif

  // Check if a module test was selected at compile time
  module_test_t selected_test = module_tests_get_compile_time_selection();

  if (selected_test != MODULE_TEST_NONE_ID) {
    // TEST MODE: Run specific module test
    // This allows testing modules in isolation
    module_tests_init();
    module_tests_run(selected_test);
    // Note: most tests run forever and don't return
  }

  // PRODUCTION MODE: Run full application
  // Project entrypoint (kept in App/ to survive CubeMX regen)
  /* MIOS32-STYLE: No dbg_printf - use fixed strings only */
  dbg_print("[DEFAULT_TASK] Calling app_entry_start()...\r\n");
  app_entry_start();

  // CRITICAL: This line should NEVER be reached!
  // app_entry_start() has an infinite loop and should never return
  dbg_print("[DEFAULT_TASK] FATAL: app_entry_start() returned! This is impossible!\r\n");
  dbg_print("[DEFAULT_TASK] Entering fallback infinite loop\r\n");

  /* Infinite loop */
  uint32_t loop_count = 0;
  for(;;)
  {
    osDelay(1);
    loop_count++;
    if (loop_count % 10000 == 0) {
      /* MIOS32-STYLE: No dbg_printf - use fixed strings + dbg_print_u32 */
      dbg_print("[DEFAULT_TASK] FATAL: Still in fallback loop! Count: ");
      dbg_print_u32(loop_count);
      dbg_print("\r\n");
    }
  }

  /* USER CODE BEGIN DefaultTask_Exit */
  // SHOULD NEVER REACH HERE!
  // If we do, something catastrophic happened (stack overflow, heap corruption, hard fault)
#if defined(MODULE_DEBUG_OUTPUT) && MODULE_DEBUG_OUTPUT == DEBUG_OUTPUT_UART
  dbg_print("[FATAL] DefaultTask infinite loop exited!\r\n");
  dbg_print("[FATAL] This should be impossible - check stack/heap!\r\n");
  dbg_print("[FATAL] DefaultTask stack: 2KB allocated\r\n");
#endif

  // Halt system for debugging
  Error_Handler();
  /* USER CODE END DefaultTask_Exit */

  /* USER CODE END 5 */
}

void HAL_TIM_PeriodElapsedCallback(TIM_HandleTypeDef *htim)
{
  if (htim->Instance == TIM6)
  {
    HAL_IncTick();
  }
}

void Error_Handler(void)
{
  __disable_irq();
  while (1)
  {
  }
}
